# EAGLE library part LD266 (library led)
LED BLOCK 6 LEDs, Siemens

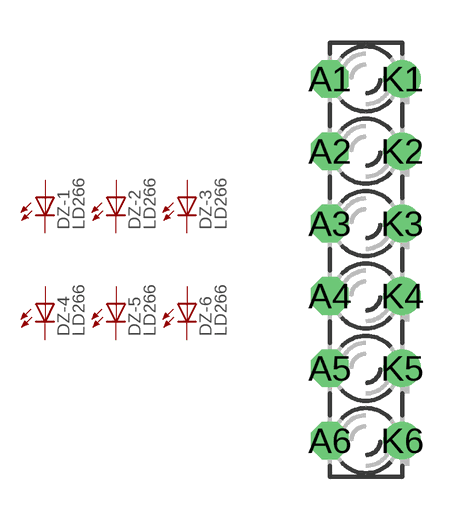
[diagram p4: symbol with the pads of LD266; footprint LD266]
Designator prefix DZ; gates -1=LED -2=LED -3=LED -4=LED -5=LED -6=LED

## LD266  [LD266]
A1  -1:A  pas
A2  -2:A  pas
A3  -3:A  pas
A4  -4:A  pas
A5  -5:A  pas
A6  -6:A  pas
K1  -1:C  pas
K2  -2:C  pas
K3  -3:C  pas
K4  -4:C  pas
K5  -5:C  pas
K6  -6:C  pas

## Footprint LD266 (pad centres in mm)
LED BLOCK 6 LEDs, Siemens
drill 0.813 octagon: A1 -1.27,6.35; A2 -1.27,3.81; A3 -1.27,1.27; A4 -1.27,-1.27; A5 -1.27,-3.81; A6 -1.27,-6.35
drill 0.813 round: K1 1.27,6.35; K2 1.27,3.81; K3 1.27,1.27; K4 1.27,-1.27; K5 1.27,-3.81; K6 1.27,-6.35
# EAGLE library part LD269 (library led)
LED BLOCK 9 LEDs, Siemens

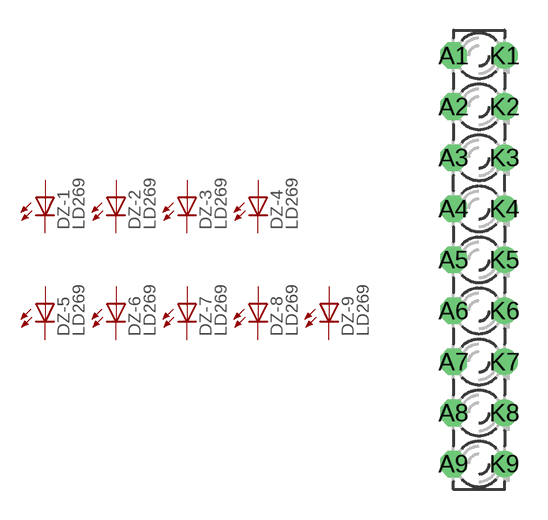
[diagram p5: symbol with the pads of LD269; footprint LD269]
Designator prefix DZ; gates -1=LED -2=LED -3=LED -4=LED -5=LED -6=LED -7=LED -8=LED -9=LED

## LD269  [LD269]
A1  -1:A  pas
A2  -2:A  pas
A3  -3:A  pas
A4  -4:A  pas
A5  -5:A  pas
A6  -6:A  pas
A7  -7:A  pas
A8  -8:A  pas
A9  -9:A  pas
K1  -1:C  pas
K2  -2:C  pas
K3  -3:C  pas
K4  -4:C  pas
K5  -5:C  pas
K6  -6:C  pas
K7  -7:C  pas
K8  -8:C  pas
K9  -9:C  pas

## Footprint LD269 (pad centres in mm)
LED BLOCK 9 LEDs, Siemens
drill 0.813 octagon: A1 -1.27,10.16; A2 -1.27,7.62; A3 -1.27,5.08; A4 -1.27,2.54; A5 -1.27,0; A6 -1.27,-2.54; A7 -1.27,-5.08; A8 -1.27,-7.62; A9 -1.27,-10.16
drill 0.813 round: K1 1.27,10.16; K2 1.27,7.62; K3 1.27,5.08; K4 1.27,2.54; K5 1.27,0; K6 1.27,-2.54; K7 1.27,-5.08; K8 1.27,-7.62; K9 1.27,-10.16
